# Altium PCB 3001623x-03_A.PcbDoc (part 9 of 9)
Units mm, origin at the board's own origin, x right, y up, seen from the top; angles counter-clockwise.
Board outline 210 x 130 mm, 9 copper layers (1-TOP, 2-GND, 3-INTOP, 4-PWR, 5-PWR, 6-INBOT, Signal_4, 7-GND, 8-BOTTOM), stack 1.979 mm thick; 755 components, 651 nets, 2980 pads, 2365 vias.
Unrouted connection lines stored in the file: 1.

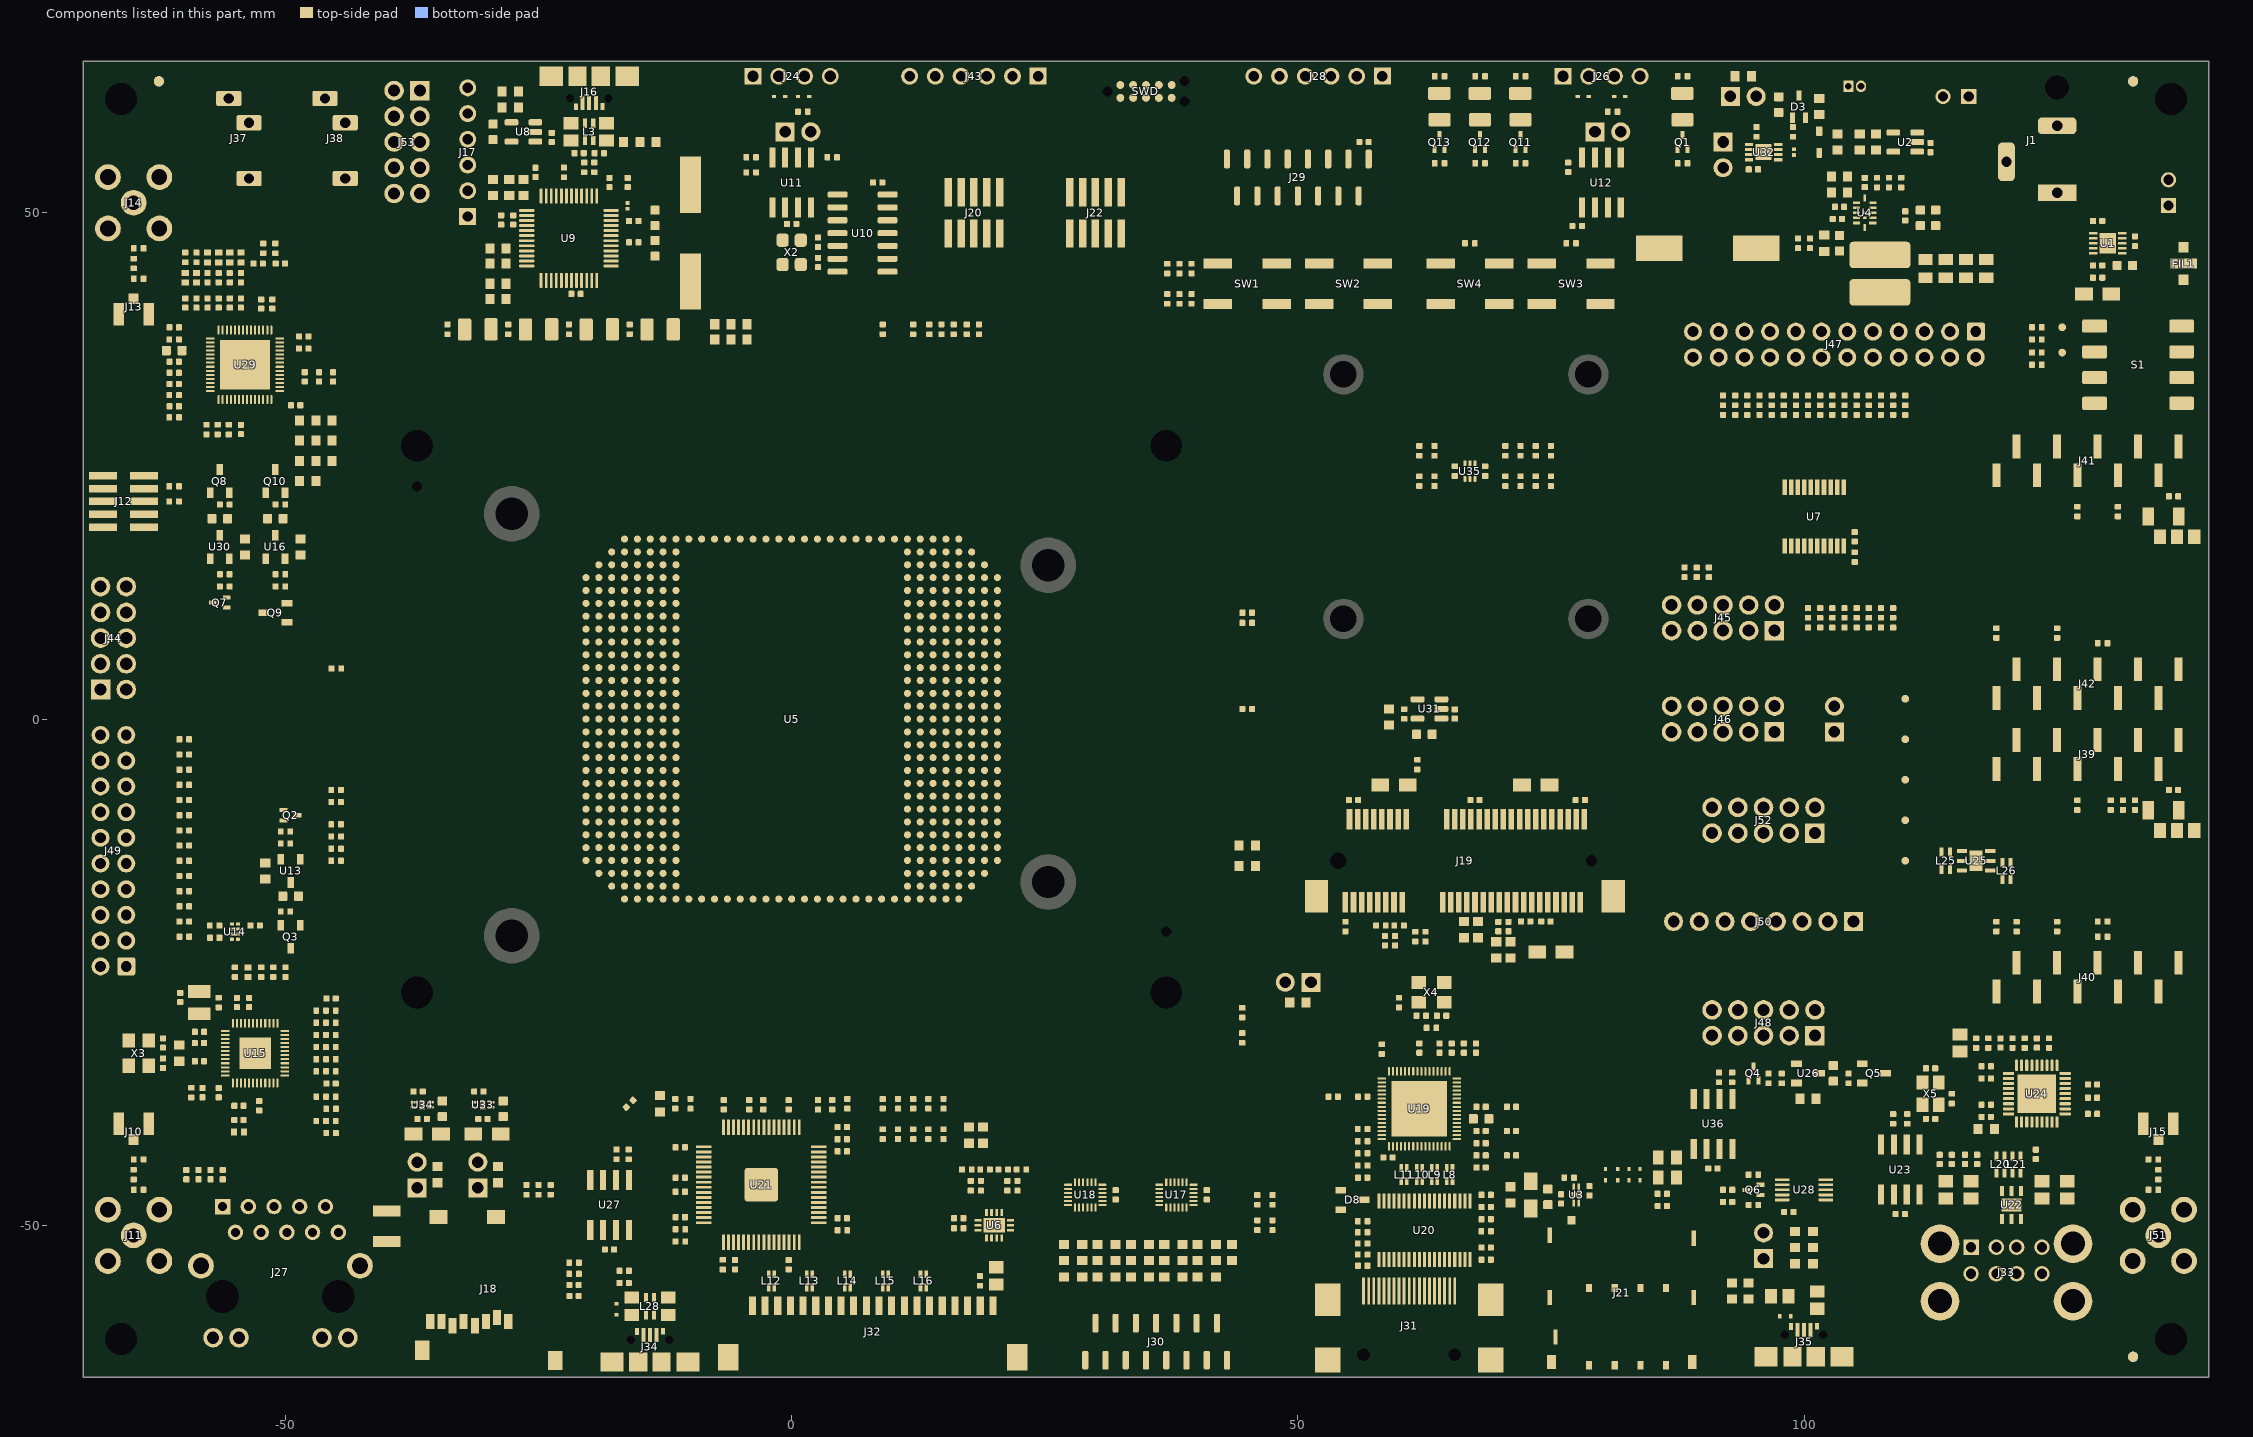
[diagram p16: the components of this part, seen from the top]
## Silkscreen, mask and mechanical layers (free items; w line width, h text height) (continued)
Drill Drawing:
  drawing of 186 lines, arcs and shapes, not listed
  text ".Layer_Name" at 127.4,-103.575 h2.54
  text "Symbol" at 129.179,-111.53 h1.83
  text "Count" at 142.028,-111.53 h1.83
  text "Hole Size" at 158.533,-111.53 h1.83
  text "Plated" at 187.735,-111.53 h1.83
  text "Hole Type" at 200.584,-111.53 h1.83
  text "Drill Layer Pair" at 219.223,-111.53 h1.83
  text "Via/Pad" at 249.44,-111.53 h1.83
  text "Pad Shape" at 264.422,-111.53 h1.83
  text "Template" at 292.1,-111.53 h1.83
  text "Description" at 322.825,-111.53 h1.83
  text "Hole Tolerance (+)" at 344.511,-111.53 h1.83
  text "Hole Tolerance (-)" at 378.384,-111.53 h1.83
  text "1" at 142.028,-115.34 h1.52
  text "1.100mm (43.31mil)" at 158.533,-115.34 h1.52
  text "NPTH" at 187.735,-115.34 h1.52
  text "Round" at 200.584,-115.34 h1.52
  text "1-TOP - 8-BOTTOM" at 219.223,-115.34 h1.52
  text "Pad" at 249.44,-115.34 h1.52
  text "Rounded" at 264.422,-115.34 h1.52
  text "c0hn110" at 292.1,-115.34 h1.52
  text "P" at 128.44,-115.594 h1.69
  text "1" at 142.028,-119.15 h1.52
  text "1.600mm (62.99mil)" at 158.533,-119.15 h1.52
  text "NPTH" at 187.735,-119.15 h1.52
  text "Round" at 200.584,-119.15 h1.52
  text "1-TOP - 8-BOTTOM" at 219.223,-119.15 h1.52
  text "Pad" at 249.44,-119.15 h1.52
  text "Rounded" at 264.422,-119.15 h1.52
  text "c0hn160" at 292.1,-119.15 h1.52
  text "E" at 128.44,-119.404 h1.69
  text "1" at 142.028,-122.96 h1.52
  text "2.362mm (93.00mil)" at 158.533,-122.96 h1.52
  text "NPTH" at 187.735,-122.96 h1.52
  text "Round" at 200.584,-122.96 h1.52
  text "1-TOP - 8-BOTTOM" at 219.223,-122.96 h1.52
  text "Pad" at 249.44,-122.96 h1.52
  text "Rounded" at 264.422,-122.96 h1.52
  text "c0hn236" at 292.1,-122.96 h1.52
  text "T" at 128.44,-123.214 h1.69
  text "2" at 142.028,-126.77 h1.52
  text "0.650mm (25.59mil)" at 158.533,-126.77 h1.52
  text "PTH" at 187.735,-126.77 h1.52
  text "Round" at 200.584,-126.77 h1.52
  text "1-TOP - 8-BOTTOM" at 219.223,-126.77 h1.52
  text "Pad" at 249.44,-126.77 h1.52
  text "(Mixed)" at 264.422,-126.77 h1.52
  text "(Mixed)" at 292.1,-126.77 h1.52
  text "\" at 128.44,-130.552 h1.69
  text "2" at 142.028,-130.58 h1.52
  text "1.270mm (50.00mil)" at 158.533,-130.58 h1.52
  text "NPTH" at 187.735,-130.58 h1.52
  text "Round" at 200.584,-130.58 h1.52
  text "1-TOP - 8-BOTTOM" at 219.223,-130.58 h1.52
  text "Pad" at 249.44,-130.58 h1.52
  text "Rounded" at 264.422,-130.58 h1.52
  text "c0hn127" at 292.1,-130.58 h1.52
  text "2" at 142.028,-134.39 h1.52
  text "1.600mm (63.00mil)" at 158.533,-134.39 h1.52
  text "PTH" at 187.735,-134.39 h1.52
  text "Round" at 200.584,-134.39 h1.52
  text "1-TOP - 8-BOTTOM" at 219.223,-134.39 h1.52
  text "Pad" at 249.44,-134.39 h1.52
  text "Rounded" at 264.422,-134.39 h1.52
  text "c254h160m264" at 292.1,-134.39 h1.52
  text "H" at 128.44,-134.644 h1.69
  text "2" at 142.028,-138.2 h1.52
  text "3.250mm (127.95mil)" at 158.533,-138.2 h1.52
  text "NPTH" at 187.735,-138.2 h1.52
  text "Round" at 200.584,-138.2 h1.52
  text "1-TOP - 8-BOTTOM" at 219.223,-138.2 h1.52
  text "Pad" at 249.44,-138.2 h1.52
  text "Rounded" at 264.422,-138.2 h1.52
  text "c0hn325m335" at 292.1,-138.2 h1.52
  text "G" at 128.44,-138.454 h1.69
  text "3" at 142.028,-142.01 h1.52
  text "0.991mm (39.00mil)" at 158.533,-142.01 h1.52
  text "NPTH" at 187.735,-142.01 h1.52
  text "Round" at 200.584,-142.01 h1.52
  text "1-TOP - 8-BOTTOM" at 219.223,-142.01 h1.52
  text "Pad" at 249.44,-142.01 h1.52
  text "Rounded" at 264.422,-142.01 h1.52
  text "c0hn99m109" at 292.1,-142.01 h1.52
  text "3" at 142.028,-145.82 h1.52
  text "1.016mm (40.00mil)" at 158.533,-145.82 h1.52
  text "PTH" at 187.735,-145.82 h1.52
  text "Slot" at 200.584,-145.82 h1.52
  text "1-TOP - 8-BOTTOM" at 219.223,-145.82 h1.52
  text "Pad" at 249.44,-145.82 h1.52
  text "Rectangle" at 264.422,-145.82 h1.52
  text "(Mixed)" at 292.1,-145.82 h1.52
  text "S" at 128.44,-146.074 h1.69
  text "3" at 142.028,-149.63 h1.52
  text "1.400mm (55.12mil)" at 158.533,-149.63 h1.52
  text "PTH" at 187.735,-149.63 h1.52
  text "Round" at 200.584,-149.63 h1.52
  text "1-TOP - 8-BOTTOM" at 219.223,-149.63 h1.52
  text "Pad" at 249.44,-149.63 h1.52
  text "Rounded" at 264.422,-149.63 h1.52
  text "c254h140" at 292.1,-149.63 h1.52
  text "Y" at 128.44,-149.884 h1.69
  text "4" at 142.028,-153.44 h1.52
  text "1.020mm (40.16mil)" at 158.533,-153.44 h1.52
  text "PTH" at 187.735,-153.44 h1.52
  text "Round" at 200.584,-153.44 h1.52
  text "1-TOP - 8-BOTTOM" at 219.223,-153.44 h1.52
  text "Pad" at 249.44,-153.44 h1.52
  text "(Mixed)" at 264.422,-153.44 h1.52
  text "(Mixed)" at 292.1,-153.44 h1.52
  text "4" at 142.028,-157.25 h1.52
  text "2.362mm (93.00mil)" at 158.533,-157.25 h1.52
  text "PTH" at 187.735,-157.25 h1.52
  text "Round" at 200.584,-157.25 h1.52
  text "1-TOP - 8-BOTTOM" at 219.223,-157.25 h1.52
  text "Pad" at 249.44,-157.25 h1.52
  text "Rounded" at 264.422,-157.25 h1.52
  text "c381h236" at 292.1,-157.25 h1.52
  text "O" at 128.44,-157.504 h1.69
  text "4" at 142.028,-161.06 h1.52
  text "2.600mm (102.36mil)" at 158.533,-161.06 h1.52
  text "PTH" at 187.735,-161.06 h1.52
  text "Round" at 200.584,-161.06 h1.52
  text "1-TOP - 8-BOTTOM" at 219.223,-161.06 h1.52
  text "Pad" at 249.44,-161.06 h1.52
  text "Rounded" at 264.422,-161.06 h1.52
  text "c400h260z0x550" at 292.1,-161.06 h1.52
  text "4" at 142.028,-164.87 h1.52
  text "3.150mm (124.02mil)" at 158.533,-164.87 h1.52
  text "PTH" at 187.735,-164.87 h1.52
  text "Round" at 200.584,-164.87 h1.52
  text "1-TOP - 8-BOTTOM" at 219.223,-164.87 h1.52
  text "Pad" at 249.44,-164.87 h1.52
  text "Rounded" at 264.422,-164.87 h1.52
  text "c0h315" at 292.1,-164.87 h1.52
  text "4" at 142.028,-168.68 h1.52
  text "3.175mm (125.00mil)" at 158.533,-168.68 h1.52
  text "NPTH" at 187.735,-168.68 h1.52
  text "Round" at 200.584,-168.68 h1.52
  text "1-TOP - 8-BOTTOM" at 219.223,-168.68 h1.52
  text "Pad" at 249.44,-168.68 h1.52
  text "Rounded" at 264.422,-168.68 h1.52
  text "c0hn318m328" at 292.1,-168.68 h1.52
  text "A" at 128.44,-168.934 h1.69
  text "4" at 142.028,-172.49 h1.52
  text "3.200mm (125.98mil)" at 158.533,-172.49 h1.52
  text "PTH" at 187.735,-172.49 h1.52
  text "Round" at 200.584,-172.49 h1.52
  text "1-TOP - 8-BOTTOM" at 219.223,-172.49 h1.52
  text "Pad" at 249.44,-172.49 h1.52
  text "Rounded" at 264.422,-172.49 h1.52
  text "c550h320z0" at 292.1,-172.49 h1.52
  text "6" at 142.028,-176.3 h1.52
  text "0.813mm (32.00mil)" at 158.533,-176.3 h1.52
  text "NPTH" at 187.735,-176.3 h1.52
  text "Round" at 200.584,-176.3 h1.52
  text "1-TOP - 8-BOTTOM" at 219.223,-176.3 h1.52
  text "Pad" at 249.44,-176.3 h1.52
  text "Rounded" at 264.422,-176.3 h1.52
  text "c0hn81m81" at 292.1,-176.3 h1.52
  text "6" at 142.028,-180.11 h1.52
  text "1.000mm (39.37mil)" at 158.533,-180.11 h1.52
  text "PTH" at 187.735,-180.11 h1.52
  text "Slot" at 200.584,-180.11 h1.52
  text "1-TOP - 8-BOTTOM" at 219.223,-180.11 h1.52
  text "Pad" at 249.44,-180.11 h1.52
  text "Rounded Rectangle" at 264.422,-180.11 h1.52
  text "r250_150h100_200r25" at 292.1,-180.11 h1.52
  text "8" at 142.028,-183.92 h1.52
  text "1.110mm (43.70mil)" at 158.533,-183.92 h1.52
  text "PTH" at 187.735,-183.92 h1.52
  text "Round" at 200.584,-183.92 h1.52
  text "1-TOP - 8-BOTTOM" at 219.223,-183.92 h1.52
  text "Pad" at 249.44,-183.92 h1.52
  text "(Mixed)" at 264.422,-183.92 h1.52
  text "(Mixed)" at 292.1,-183.92 h1.52
  text "10" at 142.028,-187.73 h1.52
  text "0.889mm (35.00mil)" at 158.533,-187.73 h1.52
  text "PTH" at 187.735,-187.73 h1.52
  text "Round" at 200.584,-187.73 h1.52
  text "1-TOP - 8-BOTTOM" at 219.223,-187.73 h1.52
  text "Pad" at 249.44,-187.73 h1.52
  text "(Mixed)" at 264.422,-187.73 h1.52
  text "(Mixed)" at 292.1,-187.73 h1.52
  text "F" at 128.44,-187.984 h1.69
  text "10" at 142.028,-191.54 h1.52
  text "1.000mm (39.37mil)" at 158.533,-191.54 h1.52
  text "PTH" at 187.735,-191.54 h1.52
  text "Round" at 200.584,-191.54 h1.52
  text "1-TOP - 8-BOTTOM" at 219.223,-191.54 h1.52
  text "Pad" at 249.44,-191.54 h1.52
  text "(Mixed)" at 264.422,-191.54 h1.52
  text "(Mixed)" at 292.1,-191.54 h1.52
  text "12" at 142.028,-195.35 h1.52
  text "1.549mm (61.00mil)" at 158.533,-195.35 h1.52
  text "PTH" at 187.735,-195.35 h1.52
  text "Round" at 200.584,-195.35 h1.52
  text "1-TOP - 8-BOTTOM" at 219.223,-195.35 h1.52
  text "Pad" at 249.44,-195.35 h1.52
  text "Rounded" at 264.422,-195.35 h1.52
  text "c254h155" at 292.1,-195.35 h1.52
  text "X" at 128.44,-195.604 h1.69
  text "18" at 142.028,-199.16 h1.52
  text "1.016mm (40.00mil)" at 158.533,-199.16 h1.52
  text "PTH" at 187.735,-199.16 h1.52
  text "Round" at 200.584,-199.16 h1.52
  text "1-TOP - 8-BOTTOM" at 219.223,-199.16 h1.52
  text "Pad" at 249.44,-199.16 h1.52
  text "(Mixed)" at 264.422,-199.16 h1.52
  text "(Mixed)" at 292.1,-199.16 h1.52
  text "26" at 142.028,-202.97 h1.52
  text "1.143mm (45.00mil)" at 158.533,-202.97 h1.52
  text "PTH" at 187.735,-202.97 h1.52
  text "Round" at 200.584,-202.97 h1.52
  text "1-TOP - 8-BOTTOM" at 219.223,-202.97 h1.52
  text "Pad" at 249.44,-202.97 h1.52
  text "(Mixed)" at 264.422,-202.97 h1.52
  text "(Mixed)" at 292.1,-202.97 h1.52
  text "U" at 128.44,-203.224 h1.69
  text "44" at 142.028,-206.78 h1.52
  text "1.067mm (42.00mil)" at 158.533,-206.78 h1.52
  text "PTH" at 187.735,-206.78 h1.52
  text "Round" at 200.584,-206.78 h1.52
  text "1-TOP - 8-BOTTOM" at 219.223,-206.78 h1.52
  text "Pad" at 249.44,-206.78 h1.52
  text "(Mixed)" at 264.422,-206.78 h1.52
  text "(Mixed)" at 292.1,-206.78 h1.52
  text "D" at 128.44,-207.034 h1.69
  text "64" at 142.028,-210.59 h1.52
  text "1.194mm (47.00mil)" at 158.533,-210.59 h1.52
  text "PTH" at 187.735,-210.59 h1.52
  text "Round" at 200.584,-210.59 h1.52
  text "1-TOP - 8-BOTTOM" at 219.223,-210.59 h1.52
  text "Pad" at 249.44,-210.59 h1.52
  text "(Mixed)" at 264.422,-210.59 h1.52
  text "(Mixed)" at 292.1,-210.59 h1.52
  text "182" at 142.028,-214.4 h1.52
  text "0.300mm (11.81mil)" at 158.533,-214.4 h1.52
  text "PTH" at 187.735,-214.4 h1.52
  text "Round" at 200.584,-214.4 h1.52
  text "1-TOP - 8-BOTTOM" at 219.223,-214.4 h1.52
  text "Via" at 249.44,-214.4 h1.52
  text "Rounded" at 264.422,-214.4 h1.52
  text "v68h30m54" at 292.1,-214.4 h1.52
  text "2183" at 142.028,-218.21 h1.52
  text "0.200mm (7.87mil)" at 158.533,-218.21 h1.52
  text "PTH" at 187.735,-218.21 h1.52
  text "Round" at 200.584,-218.21 h1.52
  text "1-TOP - 8-BOTTOM" at 219.223,-218.21 h1.52
  text "Via" at 249.44,-218.21 h1.52
  text "Rounded" at 264.422,-218.21 h1.52
  text "(Mixed)" at 292.1,-218.21 h1.52
  text "2613 Total" at 142.028,-222.02 h1.52
  text "Slot definitions :" at 129.179,-225.702 h1.52
  text "Routed Path Length" at 155.409,-225.702 h1.52
  text "= Calculated from tool start centre position to tool end centre position." at 183.417,-225.702 h1.52
  text "Hole Length" at 155.409,-228.242 h1.52
  text "= Routed Path Length + Tool Size = Slot length as defined in the PCB layout" at 173.006,-228.242 h1.52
